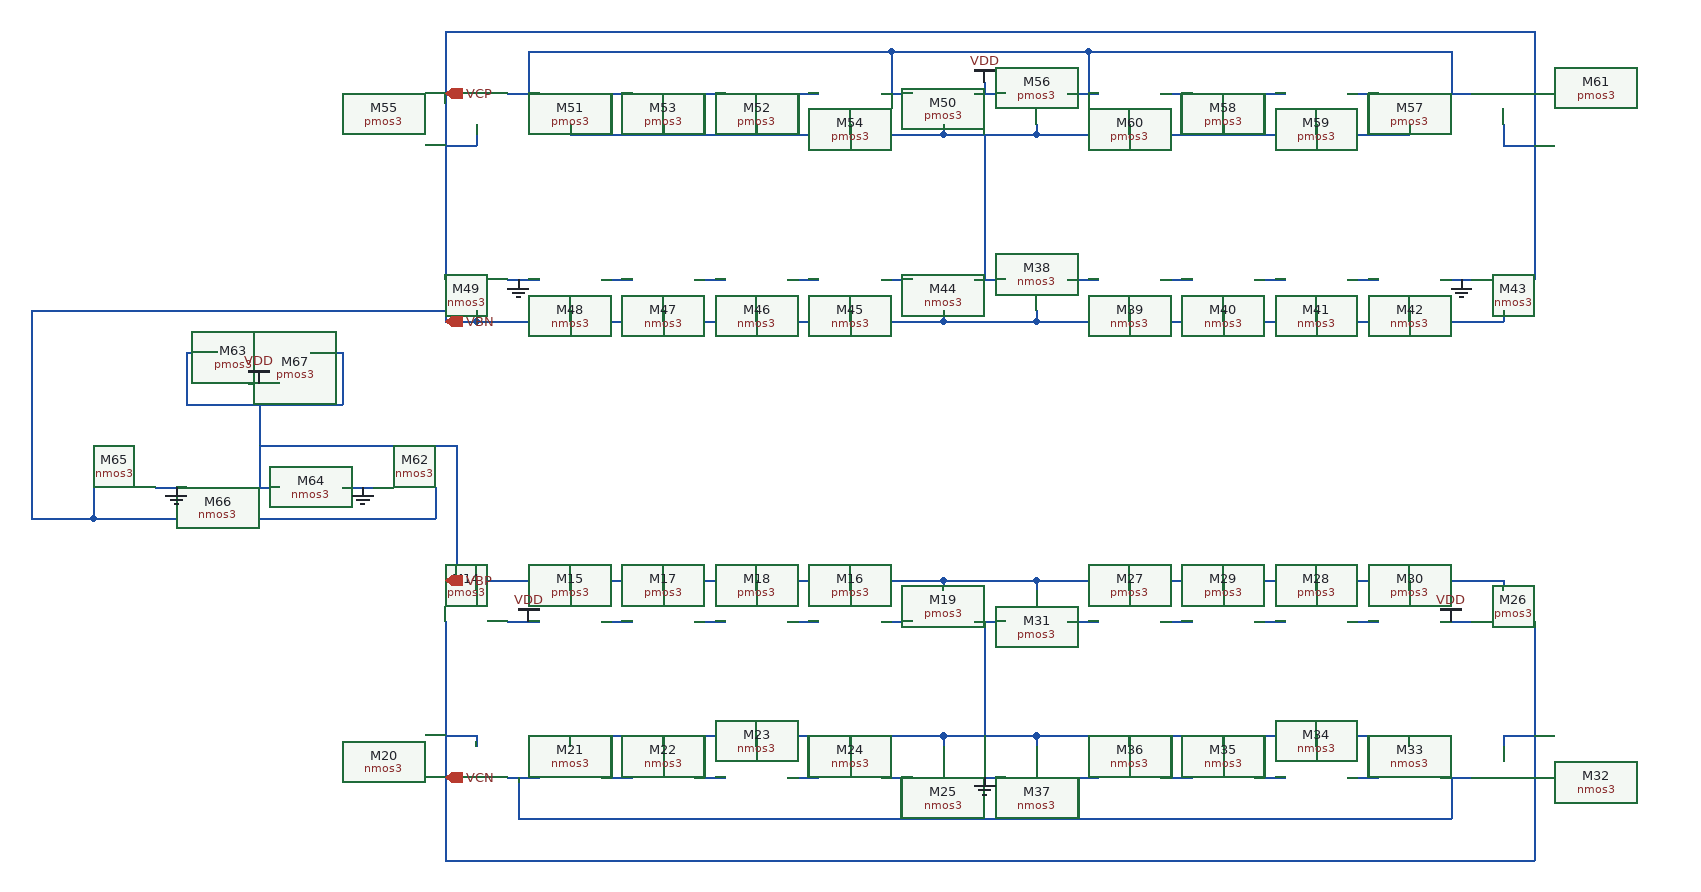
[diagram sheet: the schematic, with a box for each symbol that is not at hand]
v {xschem version=3.4.3 file_version=1.2
}
G {}
K {}
V {}
S {}
E {}
N -960 -300 -930 -300 {
lab=VDD}
N -870 -300 -840 -300 {
lab=#net1}
N -780 -300 -750 -300 {
lab=#net2}
N -690 -300 -660 -300 {
lab=#net3}
N -600 -300 -570 -300 {
lab=#net4}
N -900 -340 -900 -330 {
lab=VBP}
N -810 -340 -810 -330 {
lab=VBP}
N -720 -340 -720 -330 {
lab=VBP}
N -990 -340 -990 -330 {
lab=VBP}
N -630 -340 -630 -330 {
lab=VBP}
N -540 -340 -540 -330 {
lab=VBP}
N -1020 -340 -540 -340 {
lab=VBP}
N -960 -150 -930 -150 {
lab=#net5}
N -870 -150 -840 -150 {
lab=#net6}
N -780 -150 -750 -150 {
lab=#net6}
N -690 -150 -660 -150 {
lab=#net6}
N -600 -150 -570 -150 {
lab=#net5}
N -990 -190 -990 -180 {
lab=VCN}
N -900 -190 -900 -180 {
lab=#net6}
N -810 -190 -810 -180 {
lab=#net6}
N -720 -190 -720 -180 {
lab=#net6}
N -630 -190 -630 -180 {
lab=#net6}
N -540 -190 -540 -180 {
lab=#net6}
N -900 -190 -540 -190 {
lab=#net6}
N -60 -300 -30 -300 {
lab=VDD}
N -150 -300 -120 -300 {
lab=#net7}
N -240 -300 -210 -300 {
lab=#net8}
N -330 -300 -300 -300 {
lab=#net9}
N -420 -300 -390 -300 {
lab=#net10}
N -90 -340 -90 -330 {
lab=VBP}
N -180 -340 -180 -330 {
lab=VBP}
N -270 -340 -270 -330 {
lab=VBP}
N 0 -340 0 -330 {
lab=VBP}
N -360 -340 -360 -330 {
lab=VBP}
N -450 -340 -450 -330 {
lab=VBP}
N -60 -150 -30 -150 {
lab=#net5}
N -150 -150 -120 -150 {
lab=#net6}
N -240 -150 -210 -150 {
lab=#net6}
N -330 -150 -300 -150 {
lab=#net6}
N -420 -150 -390 -150 {
lab=#net5}
N 0 -190 0 -180 {
lab=VCN}
N -90 -190 -90 -180 {
lab=#net6}
N -180 -190 -180 -180 {
lab=#net6}
N -270 -190 -270 -180 {
lab=#net6}
N -360 -190 -360 -180 {
lab=#net6}
N -450 -190 -450 -180 {
lab=#net6}
N -450 -190 -90 -190 {
lab=#net6}
N -510 -150 -480 -150 {
lab=GND}
N -540 -190 -450 -190 {
lab=#net6}
N -510 -300 -480 -300 {
lab=#net6}
N -1020 -300 -1020 -150 {
lab=VCN}
N -1020 -190 -990 -190 {
lab=VCN}
N 30 -300 30 -150 {
lab=VCN}
N 0 -190 30 -190 {
lab=VCN}
N -500 -300 -500 -190 {
lab=#net6}
N -950 -150 -950 -110 {
lab=#net5}
N -950 -110 -760 -110 {
lab=#net5}
N -760 -110 -50 -110 {
lab=#net5}
N -50 -150 -50 -110 {
lab=#net5}
N -860 -190 -860 -150 {
lab=#net6}
N -770 -190 -770 -150 {
lab=#net6}
N -580 -150 -580 -110 {
lab=#net5}
N -670 -190 -670 -150 {
lab=#net6}
N -410 -150 -410 -110 {
lab=#net5}
N -320 -190 -320 -150 {
lab=#net6}
N -230 -190 -230 -150 {
lab=#net6}
N -130 -190 -130 -150 {
lab=#net6}
N -450 -340 0 -340 {
lab=VBP}
N -990 -600 -990 -590 {
lab=VBN}
N -900 -600 -900 -590 {
lab=VBN}
N -810 -600 -810 -590 {
lab=VBN}
N -720 -600 -720 -590 {
lab=VBN}
N -630 -600 -630 -590 {
lab=VBN}
N -540 -600 -540 -590 {
lab=VBN}
N -990 -590 -540 -590 {
lab=VBN}
N -960 -630 -930 -630 {
lab=GND}
N -870 -630 -840 -630 {
lab=#net11}
N -780 -630 -750 -630 {
lab=#net12}
N -690 -630 -660 -630 {
lab=#net13}
N -600 -630 -570 -630 {
lab=#net14}
N -960 -810 -930 -810 {
lab=#net15}
N -870 -810 -840 -810 {
lab=#net16}
N -780 -810 -750 -810 {
lab=#net16}
N -690 -810 -660 -810 {
lab=#net16}
N -600 -810 -570 -810 {
lab=#net15}
N -1020 -810 -1020 -630 {
lab=VCP}
N -990 -780 -990 -760 {
lab=VCP}
N -1020 -760 -990 -760 {
lab=VCP}
N -900 -780 -900 -770 {
lab=#net16}
N -900 -770 -540 -770 {
lab=#net16}
N -540 -780 -540 -770 {
lab=#net16}
N -860 -810 -860 -770 {
lab=#net16}
N -940 -850 -940 -810 {
lab=#net15}
N -940 -850 -590 -850 {
lab=#net15}
N -590 -850 -590 -810 {
lab=#net15}
N -810 -780 -810 -770 {
lab=#net16}
N -720 -780 -720 -770 {
lab=#net16}
N -630 -780 -630 -770 {
lab=#net16}
N -500 -820 -500 -810 {
lab=VDD}
N 0 -600 0 -590 {
lab=VBN}
N -90 -600 -90 -590 {
lab=VBN}
N -180 -600 -180 -590 {
lab=VBN}
N -270 -600 -270 -590 {
lab=VBN}
N -360 -600 -360 -590 {
lab=VBN}
N -450 -600 -450 -590 {
lab=VBN}
N -450 -590 0 -590 {
lab=VBN}
N -60 -630 -30 -630 {
lab=GND}
N -150 -630 -120 -630 {
lab=#net17}
N -240 -630 -210 -630 {
lab=#net18}
N -330 -630 -300 -630 {
lab=#net19}
N -420 -630 -390 -630 {
lab=#net20}
N -60 -810 -30 -810 {
lab=#net15}
N -150 -810 -120 -810 {
lab=#net16}
N -240 -810 -210 -810 {
lab=#net16}
N -330 -810 -300 -810 {
lab=#net16}
N -420 -810 -390 -810 {
lab=#net15}
N 30 -810 30 -630 {
lab=VCP}
N 0 -780 0 -760 {
lab=VCP}
N 0 -760 30 -760 {
lab=VCP}
N -90 -780 -90 -770 {
lab=#net16}
N -450 -770 -90 -770 {
lab=#net16}
N -450 -780 -450 -770 {
lab=#net16}
N -130 -810 -130 -770 {
lab=#net16}
N -50 -850 -50 -810 {
lab=#net15}
N -400 -850 -50 -850 {
lab=#net15}
N -400 -850 -400 -810 {
lab=#net15}
N -180 -780 -180 -770 {
lab=#net16}
N -270 -780 -270 -770 {
lab=#net16}
N -360 -780 -360 -770 {
lab=#net16}
N -510 -810 -480 -810 {
lab=VDD}
N -510 -630 -480 -630 {
lab=#net16}
N -540 -770 -450 -770 {
lab=#net16}
N -500 -770 -500 -630 {
lab=#net16}
N -590 -850 -400 -850 {
lab=#net15}
N 30 -870 30 -810 {
lab=VCP}
N -1020 -870 30 -870 {
lab=VCP}
N -1020 -870 -1020 -800 {
lab=VCP}
N -1020 -150 -1020 -70 {
lab=VCN}
N -1020 -70 30 -70 {
lab=VCN}
N 30 -150 30 -70 {
lab=VCN}
N -1020 -590 -990 -590 {
lab=VBN}
N -1030 -430 -1030 -400 {
lab=VBN}
N -1150 -400 -1030 -400 {
lab=VBN}
N -1120 -430 -1090 -430 {
lab=GND}
N -1360 -430 -1360 -400 {
lab=VBN}
N -1360 -400 -1240 -400 {
lab=VBN}
N -1300 -430 -1270 -430 {
lab=GND}
N -1210 -430 -1180 -430 {
lab=#net21}
N -1240 -400 -1150 -400 {
lab=VBN}
N -1210 -530 -1180 -530 {
lab=VDD}
N -1270 -560 -1270 -530 {
lab=#net21}
N -1270 -560 -1240 -560 {
lab=#net21}
N -1150 -560 -1120 -560 {
lab=#net21}
N -1120 -560 -1120 -530 {
lab=#net21}
N -1270 -530 -1270 -510 {
lab=#net21}
N -1270 -510 -1120 -510 {
lab=#net21}
N -1120 -530 -1120 -510 {
lab=#net21}
N -1200 -510 -1200 -430 {
lab=#net21}
N -540 -590 -450 -590 {
lab=VBN}
N -540 -340 -450 -340 {
lab=VBP}
N -770 -810 -770 -770 {
lab=#net16}
N -680 -810 -680 -770 {
lab=#net16}
N -310 -810 -310 -770 {
lab=#net16}
N -230 -810 -230 -770 {
lab=#net16}
N -1200 -470 -1010 -470 {}
N -1010 -470 -1010 -340 {}
N -1420 -400 -1360 -400 {}
N -1420 -600 -1420 -400 {}
N -1420 -600 -1020 -600 {}
N -1020 -600 -1020 -590 {}
C {madvlsi/pmos3.sym} -990 -300 1 0 {name=M14
L=0.5
W=12
body=VDD
nf=1
mult=1
ad="'int((nf+1)/2) * W/nf * 0.29'" 
pd="'2*int((nf+1)/2) * (W/nf + 0.29)'"
as="'int((nf+2)/2) * W/nf * 0.29'" 
ps="'2*int((nf+2)/2) * (W/nf + 0.29)'"
nrd="'0.29 / W'" nrs="'0.29 / W'"
sa=0 sb=0 sd=0
model=pfet_01v8
spiceprefix=X
}
C {madvlsi/pmos3.sym} -630 -300 1 0 {name=M16
L=0.5
W=12
body=VDD
nf=1
mult=1
ad="'int((nf+1)/2) * W/nf * 0.29'" 
pd="'2*int((nf+1)/2) * (W/nf + 0.29)'"
as="'int((nf+2)/2) * W/nf * 0.29'" 
ps="'2*int((nf+2)/2) * (W/nf + 0.29)'"
nrd="'0.29 / W'" nrs="'0.29 / W'"
sa=0 sb=0 sd=0
model=pfet_01v8
spiceprefix=X
}
C {madvlsi/pmos3.sym} -810 -300 1 0 {name=M17
L=0.5
W=12
body=VDD
nf=1
mult=1
ad="'int((nf+1)/2) * W/nf * 0.29'" 
pd="'2*int((nf+1)/2) * (W/nf + 0.29)'"
as="'int((nf+2)/2) * W/nf * 0.29'" 
ps="'2*int((nf+2)/2) * (W/nf + 0.29)'"
nrd="'0.29 / W'" nrs="'0.29 / W'"
sa=0 sb=0 sd=0
model=pfet_01v8
spiceprefix=X
}
C {madvlsi/pmos3.sym} -720 -300 1 0 {name=M18
L=0.5
W=12
body=VDD
nf=1
mult=1
ad="'int((nf+1)/2) * W/nf * 0.29'" 
pd="'2*int((nf+1)/2) * (W/nf + 0.29)'"
as="'int((nf+2)/2) * W/nf * 0.29'" 
ps="'2*int((nf+2)/2) * (W/nf + 0.29)'"
nrd="'0.29 / W'" nrs="'0.29 / W'"
sa=0 sb=0 sd=0
model=pfet_01v8
spiceprefix=X
}
C {madvlsi/pmos3.sym} -900 -300 1 0 {name=M15
L=0.5
W=12
body=VDD
nf=1
mult=1
ad="'int((nf+1)/2) * W/nf * 0.29'" 
pd="'2*int((nf+1)/2) * (W/nf + 0.29)'"
as="'int((nf+2)/2) * W/nf * 0.29'" 
ps="'2*int((nf+2)/2) * (W/nf + 0.29)'"
nrd="'0.29 / W'" nrs="'0.29 / W'"
sa=0 sb=0 sd=0
model=pfet_01v8
spiceprefix=X
}
C {madvlsi/pmos3.sym} -540 -300 1 0 {name=M19
L=0.5
W=12
body=VDD
nf=1
mult=1
ad="'int((nf+1)/2) * W/nf * 0.29'" 
pd="'2*int((nf+1)/2) * (W/nf + 0.29)'"
as="'int((nf+2)/2) * W/nf * 0.29'" 
ps="'2*int((nf+2)/2) * (W/nf + 0.29)'"
nrd="'0.29 / W'" nrs="'0.29 / W'"
sa=0 sb=0 sd=0
model=pfet_01v8
spiceprefix=X
}
C {madvlsi/vdd.sym} -940 -300 0 0 {name=l4 lab=VDD}
C {madvlsi/nmos3.sym} -990 -150 3 1 {name=M20
L=0.5
W=12
body=GND
nf=1
mult=1
ad="'int((nf+1)/2) * W/nf * 0.29'" 
pd="'2*int((nf+1)/2) * (W/nf + 0.29)'"
as="'int((nf+2)/2) * W/nf * 0.29'" 
ps="'2*int((nf+2)/2) * (W/nf + 0.29)'"
nrd="'0.29 / W'" nrs="'0.29 / W'"
sa=0 sb=0 sd=0
model=nfet_01v8
spiceprefix=X
}
C {madvlsi/nmos3.sym} -900 -150 3 1 {name=M21
L=0.5
W=12
body=GND
nf=1
mult=1
ad="'int((nf+1)/2) * W/nf * 0.29'" 
pd="'2*int((nf+1)/2) * (W/nf + 0.29)'"
as="'int((nf+2)/2) * W/nf * 0.29'" 
ps="'2*int((nf+2)/2) * (W/nf + 0.29)'"
nrd="'0.29 / W'" nrs="'0.29 / W'"
sa=0 sb=0 sd=0
model=nfet_01v8
spiceprefix=X
}
C {madvlsi/nmos3.sym} -810 -150 3 1 {name=M22
L=0.5
W=12
body=GND
nf=1
mult=1
ad="'int((nf+1)/2) * W/nf * 0.29'" 
pd="'2*int((nf+1)/2) * (W/nf + 0.29)'"
as="'int((nf+2)/2) * W/nf * 0.29'" 
ps="'2*int((nf+2)/2) * (W/nf + 0.29)'"
nrd="'0.29 / W'" nrs="'0.29 / W'"
sa=0 sb=0 sd=0
model=nfet_01v8
spiceprefix=X
}
C {madvlsi/nmos3.sym} -720 -150 3 1 {name=M23
L=0.5
W=12
body=GND
nf=1
mult=1
ad="'int((nf+1)/2) * W/nf * 0.29'" 
pd="'2*int((nf+1)/2) * (W/nf + 0.29)'"
as="'int((nf+2)/2) * W/nf * 0.29'" 
ps="'2*int((nf+2)/2) * (W/nf + 0.29)'"
nrd="'0.29 / W'" nrs="'0.29 / W'"
sa=0 sb=0 sd=0
model=nfet_01v8
spiceprefix=X
}
C {madvlsi/nmos3.sym} -630 -150 3 1 {name=M24
L=0.5
W=12
body=GND
nf=1
mult=1
ad="'int((nf+1)/2) * W/nf * 0.29'" 
pd="'2*int((nf+1)/2) * (W/nf + 0.29)'"
as="'int((nf+2)/2) * W/nf * 0.29'" 
ps="'2*int((nf+2)/2) * (W/nf + 0.29)'"
nrd="'0.29 / W'" nrs="'0.29 / W'"
sa=0 sb=0 sd=0
model=nfet_01v8
spiceprefix=X
}
C {madvlsi/nmos3.sym} -540 -150 3 1 {name=M25
L=0.5
W=12
body=GND
nf=1
mult=1
ad="'int((nf+1)/2) * W/nf * 0.29'" 
pd="'2*int((nf+1)/2) * (W/nf + 0.29)'"
as="'int((nf+2)/2) * W/nf * 0.29'" 
ps="'2*int((nf+2)/2) * (W/nf + 0.29)'"
nrd="'0.29 / W'" nrs="'0.29 / W'"
sa=0 sb=0 sd=0
model=nfet_01v8
spiceprefix=X
}
C {madvlsi/pmos3.sym} 0 -300 3 1 {name=M26
L=0.5
W=12
body=VDD
nf=1
mult=1
ad="'int((nf+1)/2) * W/nf * 0.29'" 
pd="'2*int((nf+1)/2) * (W/nf + 0.29)'"
as="'int((nf+2)/2) * W/nf * 0.29'" 
ps="'2*int((nf+2)/2) * (W/nf + 0.29)'"
nrd="'0.29 / W'" nrs="'0.29 / W'"
sa=0 sb=0 sd=0
model=pfet_01v8
spiceprefix=X
}
C {madvlsi/pmos3.sym} -360 -300 3 1 {name=M27
L=0.5
W=12
body=VDD
nf=1
mult=1
ad="'int((nf+1)/2) * W/nf * 0.29'" 
pd="'2*int((nf+1)/2) * (W/nf + 0.29)'"
as="'int((nf+2)/2) * W/nf * 0.29'" 
ps="'2*int((nf+2)/2) * (W/nf + 0.29)'"
nrd="'0.29 / W'" nrs="'0.29 / W'"
sa=0 sb=0 sd=0
model=pfet_01v8
spiceprefix=X
}
C {madvlsi/pmos3.sym} -180 -300 3 1 {name=M28
L=0.5
W=12
body=VDD
nf=1
mult=1
ad="'int((nf+1)/2) * W/nf * 0.29'" 
pd="'2*int((nf+1)/2) * (W/nf + 0.29)'"
as="'int((nf+2)/2) * W/nf * 0.29'" 
ps="'2*int((nf+2)/2) * (W/nf + 0.29)'"
nrd="'0.29 / W'" nrs="'0.29 / W'"
sa=0 sb=0 sd=0
model=pfet_01v8
spiceprefix=X
}
C {madvlsi/pmos3.sym} -270 -300 3 1 {name=M29
L=0.5
W=12
body=VDD
nf=1
mult=1
ad="'int((nf+1)/2) * W/nf * 0.29'" 
pd="'2*int((nf+1)/2) * (W/nf + 0.29)'"
as="'int((nf+2)/2) * W/nf * 0.29'" 
ps="'2*int((nf+2)/2) * (W/nf + 0.29)'"
nrd="'0.29 / W'" nrs="'0.29 / W'"
sa=0 sb=0 sd=0
model=pfet_01v8
spiceprefix=X
}
C {madvlsi/pmos3.sym} -90 -300 3 1 {name=M30
L=0.5
W=12
body=VDD
nf=1
mult=1
ad="'int((nf+1)/2) * W/nf * 0.29'" 
pd="'2*int((nf+1)/2) * (W/nf + 0.29)'"
as="'int((nf+2)/2) * W/nf * 0.29'" 
ps="'2*int((nf+2)/2) * (W/nf + 0.29)'"
nrd="'0.29 / W'" nrs="'0.29 / W'"
sa=0 sb=0 sd=0
model=pfet_01v8
spiceprefix=X
}
C {madvlsi/pmos3.sym} -450 -300 3 1 {name=M31
L=0.5
W=12
body=VDD
nf=1
mult=1
ad="'int((nf+1)/2) * W/nf * 0.29'" 
pd="'2*int((nf+1)/2) * (W/nf + 0.29)'"
as="'int((nf+2)/2) * W/nf * 0.29'" 
ps="'2*int((nf+2)/2) * (W/nf + 0.29)'"
nrd="'0.29 / W'" nrs="'0.29 / W'"
sa=0 sb=0 sd=0
model=pfet_01v8
spiceprefix=X
}
C {madvlsi/vdd.sym} -50 -300 0 1 {name=l5 lab=VDD}
C {madvlsi/nmos3.sym} 0 -150 1 0 {name=M32
L=0.5
W=12
body=GND
nf=1
mult=1
ad="'int((nf+1)/2) * W/nf * 0.29'" 
pd="'2*int((nf+1)/2) * (W/nf + 0.29)'"
as="'int((nf+2)/2) * W/nf * 0.29'" 
ps="'2*int((nf+2)/2) * (W/nf + 0.29)'"
nrd="'0.29 / W'" nrs="'0.29 / W'"
sa=0 sb=0 sd=0
model=nfet_01v8
spiceprefix=X
}
C {madvlsi/nmos3.sym} -90 -150 1 0 {name=M33
L=0.5
W=12
body=GND
nf=1
mult=1
ad="'int((nf+1)/2) * W/nf * 0.29'" 
pd="'2*int((nf+1)/2) * (W/nf + 0.29)'"
as="'int((nf+2)/2) * W/nf * 0.29'" 
ps="'2*int((nf+2)/2) * (W/nf + 0.29)'"
nrd="'0.29 / W'" nrs="'0.29 / W'"
sa=0 sb=0 sd=0
model=nfet_01v8
spiceprefix=X
}
C {madvlsi/nmos3.sym} -180 -150 1 0 {name=M34
L=0.5
W=12
body=GND
nf=1
mult=1
ad="'int((nf+1)/2) * W/nf * 0.29'" 
pd="'2*int((nf+1)/2) * (W/nf + 0.29)'"
as="'int((nf+2)/2) * W/nf * 0.29'" 
ps="'2*int((nf+2)/2) * (W/nf + 0.29)'"
nrd="'0.29 / W'" nrs="'0.29 / W'"
sa=0 sb=0 sd=0
model=nfet_01v8
spiceprefix=X
}
C {madvlsi/nmos3.sym} -270 -150 1 0 {name=M35
L=0.5
W=12
body=GND
nf=1
mult=1
ad="'int((nf+1)/2) * W/nf * 0.29'" 
pd="'2*int((nf+1)/2) * (W/nf + 0.29)'"
as="'int((nf+2)/2) * W/nf * 0.29'" 
ps="'2*int((nf+2)/2) * (W/nf + 0.29)'"
nrd="'0.29 / W'" nrs="'0.29 / W'"
sa=0 sb=0 sd=0
model=nfet_01v8
spiceprefix=X
}
C {madvlsi/nmos3.sym} -360 -150 1 0 {name=M36
L=0.5
W=12
body=GND
nf=1
mult=1
ad="'int((nf+1)/2) * W/nf * 0.29'" 
pd="'2*int((nf+1)/2) * (W/nf + 0.29)'"
as="'int((nf+2)/2) * W/nf * 0.29'" 
ps="'2*int((nf+2)/2) * (W/nf + 0.29)'"
nrd="'0.29 / W'" nrs="'0.29 / W'"
sa=0 sb=0 sd=0
model=nfet_01v8
spiceprefix=X
}
C {madvlsi/nmos3.sym} -450 -150 1 0 {name=M37
L=0.5
W=12
body=GND
nf=1
mult=1
ad="'int((nf+1)/2) * W/nf * 0.29'" 
pd="'2*int((nf+1)/2) * (W/nf + 0.29)'"
as="'int((nf+2)/2) * W/nf * 0.29'" 
ps="'2*int((nf+2)/2) * (W/nf + 0.29)'"
nrd="'0.29 / W'" nrs="'0.29 / W'"
sa=0 sb=0 sd=0
model=nfet_01v8
spiceprefix=X
}
C {devices/opin.sym} -1020 -340 2 0 {name=p2 lab=VBP}
C {devices/opin.sym} -1020 -150 2 0 {name=p6 lab=VCN}
C {madvlsi/gnd.sym} -500 -150 0 0 {name=l6 lab=GND}
C {madvlsi/nmos3.sym} -540 -630 3 0 {name=M44
L=0.5
W=12
body=GND
nf=1
mult=1
ad="'int((nf+1)/2) * W/nf * 0.29'" 
pd="'2*int((nf+1)/2) * (W/nf + 0.29)'"
as="'int((nf+2)/2) * W/nf * 0.29'" 
ps="'2*int((nf+2)/2) * (W/nf + 0.29)'"
nrd="'0.29 / W'" nrs="'0.29 / W'"
sa=0 sb=0 sd=0
model=nfet_01v8
spiceprefix=X
}
C {madvlsi/nmos3.sym} -630 -630 3 0 {name=M45
L=0.5
W=12
body=GND
nf=1
mult=1
ad="'int((nf+1)/2) * W/nf * 0.29'" 
pd="'2*int((nf+1)/2) * (W/nf + 0.29)'"
as="'int((nf+2)/2) * W/nf * 0.29'" 
ps="'2*int((nf+2)/2) * (W/nf + 0.29)'"
nrd="'0.29 / W'" nrs="'0.29 / W'"
sa=0 sb=0 sd=0
model=nfet_01v8
spiceprefix=X
}
C {madvlsi/nmos3.sym} -720 -630 3 0 {name=M46
L=0.5
W=12
body=GND
nf=1
mult=1
ad="'int((nf+1)/2) * W/nf * 0.29'" 
pd="'2*int((nf+1)/2) * (W/nf + 0.29)'"
as="'int((nf+2)/2) * W/nf * 0.29'" 
ps="'2*int((nf+2)/2) * (W/nf + 0.29)'"
nrd="'0.29 / W'" nrs="'0.29 / W'"
sa=0 sb=0 sd=0
model=nfet_01v8
spiceprefix=X
}
C {madvlsi/nmos3.sym} -810 -630 3 0 {name=M47
L=0.5
W=12
body=GND
nf=1
mult=1
ad="'int((nf+1)/2) * W/nf * 0.29'" 
pd="'2*int((nf+1)/2) * (W/nf + 0.29)'"
as="'int((nf+2)/2) * W/nf * 0.29'" 
ps="'2*int((nf+2)/2) * (W/nf + 0.29)'"
nrd="'0.29 / W'" nrs="'0.29 / W'"
sa=0 sb=0 sd=0
model=nfet_01v8
spiceprefix=X
}
C {madvlsi/nmos3.sym} -900 -630 3 0 {name=M48
L=0.5
W=12
body=GND
nf=1
mult=1
ad="'int((nf+1)/2) * W/nf * 0.29'" 
pd="'2*int((nf+1)/2) * (W/nf + 0.29)'"
as="'int((nf+2)/2) * W/nf * 0.29'" 
ps="'2*int((nf+2)/2) * (W/nf + 0.29)'"
nrd="'0.29 / W'" nrs="'0.29 / W'"
sa=0 sb=0 sd=0
model=nfet_01v8
spiceprefix=X
}
C {madvlsi/nmos3.sym} -990 -630 3 0 {name=M49
L=0.5
W=12
body=GND
nf=1
mult=1
ad="'int((nf+1)/2) * W/nf * 0.29'" 
pd="'2*int((nf+1)/2) * (W/nf + 0.29)'"
as="'int((nf+2)/2) * W/nf * 0.29'" 
ps="'2*int((nf+2)/2) * (W/nf + 0.29)'"
nrd="'0.29 / W'" nrs="'0.29 / W'"
sa=0 sb=0 sd=0
model=nfet_01v8
spiceprefix=X
}
C {madvlsi/pmos3.sym} -540 -810 3 0 {name=M50
L=0.5
W=12
body=VDD
nf=1
mult=1
ad="'int((nf+1)/2) * W/nf * 0.29'" 
pd="'2*int((nf+1)/2) * (W/nf + 0.29)'"
as="'int((nf+2)/2) * W/nf * 0.29'" 
ps="'2*int((nf+2)/2) * (W/nf + 0.29)'"
nrd="'0.29 / W'" nrs="'0.29 / W'"
sa=0 sb=0 sd=0
model=pfet_01v8
spiceprefix=X
}
C {madvlsi/pmos3.sym} -900 -810 3 0 {name=M51
L=0.5
W=12
body=VDD
nf=1
mult=1
ad="'int((nf+1)/2) * W/nf * 0.29'" 
pd="'2*int((nf+1)/2) * (W/nf + 0.29)'"
as="'int((nf+2)/2) * W/nf * 0.29'" 
ps="'2*int((nf+2)/2) * (W/nf + 0.29)'"
nrd="'0.29 / W'" nrs="'0.29 / W'"
sa=0 sb=0 sd=0
model=pfet_01v8
spiceprefix=X
}
C {madvlsi/pmos3.sym} -720 -810 3 0 {name=M52
L=0.5
W=12
body=VDD
nf=1
mult=1
ad="'int((nf+1)/2) * W/nf * 0.29'" 
pd="'2*int((nf+1)/2) * (W/nf + 0.29)'"
as="'int((nf+2)/2) * W/nf * 0.29'" 
ps="'2*int((nf+2)/2) * (W/nf + 0.29)'"
nrd="'0.29 / W'" nrs="'0.29 / W'"
sa=0 sb=0 sd=0
model=pfet_01v8
spiceprefix=X
}
C {madvlsi/pmos3.sym} -810 -810 3 0 {name=M53
L=0.5
W=12
body=VDD
nf=1
mult=1
ad="'int((nf+1)/2) * W/nf * 0.29'" 
pd="'2*int((nf+1)/2) * (W/nf + 0.29)'"
as="'int((nf+2)/2) * W/nf * 0.29'" 
ps="'2*int((nf+2)/2) * (W/nf + 0.29)'"
nrd="'0.29 / W'" nrs="'0.29 / W'"
sa=0 sb=0 sd=0
model=pfet_01v8
spiceprefix=X
}
C {madvlsi/pmos3.sym} -630 -810 3 0 {name=M54
L=0.5
W=12
body=VDD
nf=1
mult=1
ad="'int((nf+1)/2) * W/nf * 0.29'" 
pd="'2*int((nf+1)/2) * (W/nf + 0.29)'"
as="'int((nf+2)/2) * W/nf * 0.29'" 
ps="'2*int((nf+2)/2) * (W/nf + 0.29)'"
nrd="'0.29 / W'" nrs="'0.29 / W'"
sa=0 sb=0 sd=0
model=pfet_01v8
spiceprefix=X
}
C {madvlsi/pmos3.sym} -990 -810 3 0 {name=M55
L=0.5
W=12
body=VDD
nf=1
mult=1
ad="'int((nf+1)/2) * W/nf * 0.29'" 
pd="'2*int((nf+1)/2) * (W/nf + 0.29)'"
as="'int((nf+2)/2) * W/nf * 0.29'" 
ps="'2*int((nf+2)/2) * (W/nf + 0.29)'"
nrd="'0.29 / W'" nrs="'0.29 / W'"
sa=0 sb=0 sd=0
model=pfet_01v8
spiceprefix=X
}
C {madvlsi/gnd.sym} -950 -630 0 0 {name=l8 lab=GND}
C {madvlsi/vdd.sym} -500 -820 0 1 {name=l9 lab=VDD}
C {madvlsi/nmos3.sym} -450 -630 1 1 {name=M38
L=0.5
W=12
body=GND
nf=1
mult=1
ad="'int((nf+1)/2) * W/nf * 0.29'" 
pd="'2*int((nf+1)/2) * (W/nf + 0.29)'"
as="'int((nf+2)/2) * W/nf * 0.29'" 
ps="'2*int((nf+2)/2) * (W/nf + 0.29)'"
nrd="'0.29 / W'" nrs="'0.29 / W'"
sa=0 sb=0 sd=0
model=nfet_01v8
spiceprefix=X
}
C {madvlsi/nmos3.sym} -360 -630 1 1 {name=M39
L=0.5
W=12
body=GND
nf=1
mult=1
ad="'int((nf+1)/2) * W/nf * 0.29'" 
pd="'2*int((nf+1)/2) * (W/nf + 0.29)'"
as="'int((nf+2)/2) * W/nf * 0.29'" 
ps="'2*int((nf+2)/2) * (W/nf + 0.29)'"
nrd="'0.29 / W'" nrs="'0.29 / W'"
sa=0 sb=0 sd=0
model=nfet_01v8
spiceprefix=X
}
C {madvlsi/nmos3.sym} -270 -630 1 1 {name=M40
L=0.5
W=12
body=GND
nf=1
mult=1
ad="'int((nf+1)/2) * W/nf * 0.29'" 
pd="'2*int((nf+1)/2) * (W/nf + 0.29)'"
as="'int((nf+2)/2) * W/nf * 0.29'" 
ps="'2*int((nf+2)/2) * (W/nf + 0.29)'"
nrd="'0.29 / W'" nrs="'0.29 / W'"
sa=0 sb=0 sd=0
model=nfet_01v8
spiceprefix=X
}
C {madvlsi/nmos3.sym} -180 -630 1 1 {name=M41
L=0.5
W=12
body=GND
nf=1
mult=1
ad="'int((nf+1)/2) * W/nf * 0.29'" 
pd="'2*int((nf+1)/2) * (W/nf + 0.29)'"
as="'int((nf+2)/2) * W/nf * 0.29'" 
ps="'2*int((nf+2)/2) * (W/nf + 0.29)'"
nrd="'0.29 / W'" nrs="'0.29 / W'"
sa=0 sb=0 sd=0
model=nfet_01v8
spiceprefix=X
}
C {madvlsi/nmos3.sym} -90 -630 1 1 {name=M42
L=0.5
W=12
body=GND
nf=1
mult=1
ad="'int((nf+1)/2) * W/nf * 0.29'" 
pd="'2*int((nf+1)/2) * (W/nf + 0.29)'"
as="'int((nf+2)/2) * W/nf * 0.29'" 
ps="'2*int((nf+2)/2) * (W/nf + 0.29)'"
nrd="'0.29 / W'" nrs="'0.29 / W'"
sa=0 sb=0 sd=0
model=nfet_01v8
spiceprefix=X
}
C {madvlsi/nmos3.sym} 0 -630 1 1 {name=M43
L=0.5
W=12
body=GND
nf=1
mult=1
ad="'int((nf+1)/2) * W/nf * 0.29'" 
pd="'2*int((nf+1)/2) * (W/nf + 0.29)'"
as="'int((nf+2)/2) * W/nf * 0.29'" 
ps="'2*int((nf+2)/2) * (W/nf + 0.29)'"
nrd="'0.29 / W'" nrs="'0.29 / W'"
sa=0 sb=0 sd=0
model=nfet_01v8
spiceprefix=X
}
C {madvlsi/pmos3.sym} -450 -810 1 1 {name=M56
L=0.5
W=12
body=VDD
nf=1
mult=1
ad="'int((nf+1)/2) * W/nf * 0.29'" 
pd="'2*int((nf+1)/2) * (W/nf + 0.29)'"
as="'int((nf+2)/2) * W/nf * 0.29'" 
ps="'2*int((nf+2)/2) * (W/nf + 0.29)'"
nrd="'0.29 / W'" nrs="'0.29 / W'"
sa=0 sb=0 sd=0
model=pfet_01v8
spiceprefix=X
}
C {madvlsi/pmos3.sym} -90 -810 1 1 {name=M57
L=0.5
W=12
body=VDD
nf=1
mult=1
ad="'int((nf+1)/2) * W/nf * 0.29'" 
pd="'2*int((nf+1)/2) * (W/nf + 0.29)'"
as="'int((nf+2)/2) * W/nf * 0.29'" 
ps="'2*int((nf+2)/2) * (W/nf + 0.29)'"
nrd="'0.29 / W'" nrs="'0.29 / W'"
sa=0 sb=0 sd=0
model=pfet_01v8
spiceprefix=X
}
C {madvlsi/pmos3.sym} -270 -810 1 1 {name=M58
L=0.5
W=12
body=VDD
nf=1
mult=1
ad="'int((nf+1)/2) * W/nf * 0.29'" 
pd="'2*int((nf+1)/2) * (W/nf + 0.29)'"
as="'int((nf+2)/2) * W/nf * 0.29'" 
ps="'2*int((nf+2)/2) * (W/nf + 0.29)'"
nrd="'0.29 / W'" nrs="'0.29 / W'"
sa=0 sb=0 sd=0
model=pfet_01v8
spiceprefix=X
}
C {madvlsi/pmos3.sym} -180 -810 1 1 {name=M59
L=0.5
W=12
body=VDD
nf=1
mult=1
ad="'int((nf+1)/2) * W/nf * 0.29'" 
pd="'2*int((nf+1)/2) * (W/nf + 0.29)'"
as="'int((nf+2)/2) * W/nf * 0.29'" 
ps="'2*int((nf+2)/2) * (W/nf + 0.29)'"
nrd="'0.29 / W'" nrs="'0.29 / W'"
sa=0 sb=0 sd=0
model=pfet_01v8
spiceprefix=X
}
C {madvlsi/pmos3.sym} -360 -810 1 1 {name=M60
L=0.5
W=12
body=VDD
nf=1
mult=1
ad="'int((nf+1)/2) * W/nf * 0.29'" 
pd="'2*int((nf+1)/2) * (W/nf + 0.29)'"
as="'int((nf+2)/2) * W/nf * 0.29'" 
ps="'2*int((nf+2)/2) * (W/nf + 0.29)'"
nrd="'0.29 / W'" nrs="'0.29 / W'"
sa=0 sb=0 sd=0
model=pfet_01v8
spiceprefix=X
}
C {madvlsi/pmos3.sym} 0 -810 1 1 {name=M61
L=0.5
W=12
body=VDD
nf=1
mult=1
ad="'int((nf+1)/2) * W/nf * 0.29'" 
pd="'2*int((nf+1)/2) * (W/nf + 0.29)'"
as="'int((nf+2)/2) * W/nf * 0.29'" 
ps="'2*int((nf+2)/2) * (W/nf + 0.29)'"
nrd="'0.29 / W'" nrs="'0.29 / W'"
sa=0 sb=0 sd=0
model=pfet_01v8
spiceprefix=X
}
C {madvlsi/gnd.sym} -40 -630 0 1 {name=l10 lab=GND}
C {devices/opin.sym} -1020 -810 2 0 {name=p7 lab=VCP}
C {devices/opin.sym} -1020 -590 2 0 {name=p8 lab=VBN}
C {madvlsi/nmos3.sym} -1060 -430 1 1 {name=M62
L=0.5
W=12
body=GND
nf=1
mult=1
ad="'int((nf+1)/2) * W/nf * 0.29'" 
pd="'2*int((nf+1)/2) * (W/nf + 0.29)'"
as="'int((nf+2)/2) * W/nf * 0.29'" 
ps="'2*int((nf+2)/2) * (W/nf + 0.29)'"
nrd="'0.29 / W'" nrs="'0.29 / W'"
sa=0 sb=0 sd=0
model=nfet_01v8
spiceprefix=X
}
C {madvlsi/nmos3.sym} -1150 -430 3 0 {name=M64
L=0.5
W=12
body=GND
nf=1
mult=1
ad="'int((nf+1)/2) * W/nf * 0.29'" 
pd="'2*int((nf+1)/2) * (W/nf + 0.29)'"
as="'int((nf+2)/2) * W/nf * 0.29'" 
ps="'2*int((nf+2)/2) * (W/nf + 0.29)'"
nrd="'0.29 / W'" nrs="'0.29 / W'"
sa=0 sb=0 sd=0
model=nfet_01v8
spiceprefix=X
}
C {madvlsi/nmos3.sym} -1330 -430 3 0 {name=M65
L=0.5
W=12
body=GND
nf=1
mult=1
ad="'int((nf+1)/2) * W/nf * 0.29'" 
pd="'2*int((nf+1)/2) * (W/nf + 0.29)'"
as="'int((nf+2)/2) * W/nf * 0.29'" 
ps="'2*int((nf+2)/2) * (W/nf + 0.29)'"
nrd="'0.29 / W'" nrs="'0.29 / W'"
sa=0 sb=0 sd=0
model=nfet_01v8
spiceprefix=X
}
C {madvlsi/nmos3.sym} -1240 -430 1 1 {name=M66
L=0.5
W=12
body=GND
nf=1
mult=1
ad="'int((nf+1)/2) * W/nf * 0.29'" 
pd="'2*int((nf+1)/2) * (W/nf + 0.29)'"
as="'int((nf+2)/2) * W/nf * 0.29'" 
ps="'2*int((nf+2)/2) * (W/nf + 0.29)'"
nrd="'0.29 / W'" nrs="'0.29 / W'"
sa=0 sb=0 sd=0
model=nfet_01v8
spiceprefix=X
}
C {madvlsi/pmos3.sym} -1240 -530 1 0 {name=M63
L=0.5
W=12
body=VDD
nf=1
mult=1
ad="'int((nf+1)/2) * W/nf * 0.29'" 
pd="'2*int((nf+1)/2) * (W/nf + 0.29)'"
as="'int((nf+2)/2) * W/nf * 0.29'" 
ps="'2*int((nf+2)/2) * (W/nf + 0.29)'"
nrd="'0.29 / W'" nrs="'0.29 / W'"
sa=0 sb=0 sd=0
model=pfet_01v8
spiceprefix=X
}
C {madvlsi/pmos3.sym} -1150 -530 1 0 {name=M67
L=0.5
W=12
body=VDD
nf=1
mult=1
ad="'int((nf+1)/2) * W/nf * 0.29'" 
pd="'2*int((nf+1)/2) * (W/nf + 0.29)'"
as="'int((nf+2)/2) * W/nf * 0.29'" 
ps="'2*int((nf+2)/2) * (W/nf + 0.29)'"
nrd="'0.29 / W'" nrs="'0.29 / W'"
sa=0 sb=0 sd=0
model=pfet_01v8
spiceprefix=X
}
C {madvlsi/vdd.sym} -1200 -530 0 0 {name=l12 lab=VDD}
C {madvlsi/gnd.sym} -1280 -430 0 1 {name=l11 lab=GND}
C {madvlsi/gnd.sym} -1100 -430 0 1 {name=l13 lab=GND}
